VERSION 5.7 ;
  NOWIREEXTENSIONATPIN ON ;
  DIVIDERCHAR "/" ;
  BUSBITCHARS "[]" ;
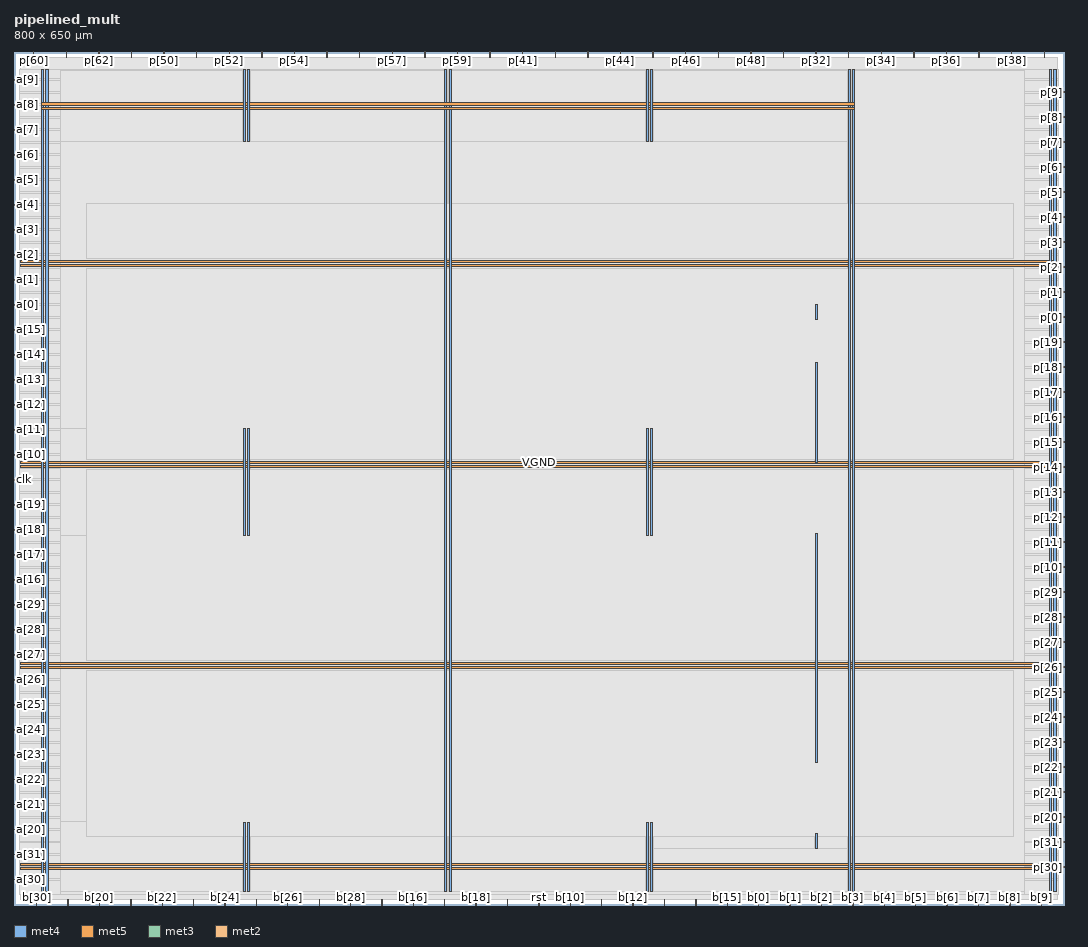
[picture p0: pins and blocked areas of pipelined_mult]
MACRO pipelined_mult
  CLASS BLOCK ;
  FOREIGN pipelined_mult ;
  ORIGIN 0.000 0.000 ;
  SIZE 800.000 BY 650.000 ;
  PIN VGND
    DIRECTION INOUT ;
    USE GROUND ;
    PORT
      LAYER met4 ;
        RECT 24.340 10.640 25.940 636.720 ;
    END
    PORT
      LAYER met4 ;
        RECT 177.940 10.640 179.540 62.995 ;
    END
    PORT
      LAYER met4 ;
        RECT 177.940 281.805 179.540 362.995 ;
    END
    PORT
      LAYER met4 ;
        RECT 177.940 581.805 179.540 636.720 ;
    END
    PORT
      LAYER met4 ;
        RECT 331.540 10.640 333.140 636.720 ;
    END
    PORT
      LAYER met4 ;
        RECT 485.140 10.640 486.740 62.995 ;
    END
    PORT
      LAYER met4 ;
        RECT 485.140 281.805 486.740 362.995 ;
    END
    PORT
      LAYER met4 ;
        RECT 485.140 581.805 486.740 636.720 ;
    END
    PORT
      LAYER met4 ;
        RECT 638.740 10.640 640.340 636.720 ;
    END
    PORT
      LAYER met4 ;
        RECT 792.340 10.640 793.940 636.720 ;
    END
    PORT
      LAYER met5 ;
        RECT 5.280 30.030 794.660 31.630 ;
    END
    PORT
      LAYER met5 ;
        RECT 5.280 183.210 794.660 184.810 ;
    END
    PORT
      LAYER met5 ;
        RECT 5.280 336.390 794.660 337.990 ;
    END
    PORT
      LAYER met5 ;
        RECT 5.280 489.570 794.660 491.170 ;
    END
    PORT
      LAYER met4 ;
        RECT 610.540 43.280 612.140 54.640 ;
    END
    PORT
      LAYER met4 ;
        RECT 610.540 108.560 612.140 283.120 ;
    END
    PORT
      LAYER met4 ;
        RECT 610.540 337.040 612.140 413.680 ;
    END
    PORT
      LAYER met4 ;
        RECT 610.540 445.840 612.140 457.200 ;
    END
    PORT
      LAYER met5 ;
        RECT 21.040 609.500 640.340 611.100 ;
    END
  END VGND
  PIN VPWR
    DIRECTION INOUT ;
    USE POWER ;
    PORT
      LAYER met4 ;
        RECT 21.040 10.640 22.640 636.720 ;
    END
    PORT
      LAYER met4 ;
        RECT 174.640 10.640 176.240 62.995 ;
    END
    PORT
      LAYER met4 ;
        RECT 174.640 281.805 176.240 362.995 ;
    END
    PORT
      LAYER met4 ;
        RECT 174.640 581.805 176.240 636.720 ;
    END
    PORT
      LAYER met4 ;
        RECT 328.240 10.640 329.840 636.720 ;
    END
    PORT
      LAYER met4 ;
        RECT 481.840 10.640 483.440 62.995 ;
    END
    PORT
      LAYER met4 ;
        RECT 481.840 281.805 483.440 362.995 ;
    END
    PORT
      LAYER met4 ;
        RECT 481.840 581.805 483.440 636.720 ;
    END
    PORT
      LAYER met4 ;
        RECT 635.440 10.640 637.040 636.720 ;
    END
    PORT
      LAYER met4 ;
        RECT 789.040 10.640 790.640 636.720 ;
    END
    PORT
      LAYER met5 ;
        RECT 5.280 26.730 794.660 28.330 ;
    END
    PORT
      LAYER met5 ;
        RECT 5.280 179.910 794.660 181.510 ;
    END
    PORT
      LAYER met5 ;
        RECT 5.280 333.090 794.660 334.690 ;
    END
    PORT
      LAYER met5 ;
        RECT 5.280 486.270 794.660 487.870 ;
    END
    PORT
      LAYER met5 ;
        RECT 21.040 606.100 640.340 607.700 ;
    END
  END VPWR
  PIN a[0]
    DIRECTION INPUT ;
    USE SIGNAL ;
    ANTENNAGATEAREA 0.682200 ;
    ANTENNADIFFAREA 0.434700 ;
    PORT
      LAYER met3 ;
        RECT 0.000 457.000 4.000 457.600 ;
    END
  END a[0]
  PIN a[10]
    DIRECTION INPUT ;
    USE SIGNAL ;
    ANTENNAGATEAREA 0.647700 ;
    ANTENNADIFFAREA 0.434700 ;
    PORT
      LAYER met3 ;
        RECT 0.000 342.760 4.000 343.360 ;
    END
  END a[10]
  PIN a[11]
    DIRECTION INPUT ;
    USE SIGNAL ;
    ANTENNAGATEAREA 0.647700 ;
    ANTENNADIFFAREA 0.434700 ;
    PORT
      LAYER met3 ;
        RECT 0.000 361.800 4.000 362.400 ;
    END
  END a[11]
  PIN a[12]
    DIRECTION INPUT ;
    USE SIGNAL ;
    ANTENNAGATEAREA 0.682200 ;
    ANTENNADIFFAREA 0.434700 ;
    PORT
      LAYER met3 ;
        RECT 0.000 380.840 4.000 381.440 ;
    END
  END a[12]
  PIN a[13]
    DIRECTION INPUT ;
    USE SIGNAL ;
    ANTENNAGATEAREA 0.647700 ;
    ANTENNADIFFAREA 0.434700 ;
    PORT
      LAYER met3 ;
        RECT 0.000 399.880 4.000 400.480 ;
    END
  END a[13]
  PIN a[14]
    DIRECTION INPUT ;
    USE SIGNAL ;
    ANTENNAGATEAREA 0.647700 ;
    ANTENNADIFFAREA 0.434700 ;
    PORT
      LAYER met3 ;
        RECT 0.000 418.920 4.000 419.520 ;
    END
  END a[14]
  PIN a[15]
    DIRECTION INPUT ;
    USE SIGNAL ;
    ANTENNAGATEAREA 0.647700 ;
    ANTENNADIFFAREA 0.434700 ;
    PORT
      LAYER met3 ;
        RECT 0.000 437.960 4.000 438.560 ;
    END
  END a[15]
  PIN a[16]
    DIRECTION INPUT ;
    USE SIGNAL ;
    ANTENNAGATEAREA 0.647700 ;
    ANTENNADIFFAREA 0.434700 ;
    PORT
      LAYER met3 ;
        RECT 0.000 247.560 4.000 248.160 ;
    END
  END a[16]
  PIN a[17]
    DIRECTION INPUT ;
    USE SIGNAL ;
    ANTENNAGATEAREA 0.647700 ;
    ANTENNADIFFAREA 0.434700 ;
    PORT
      LAYER met3 ;
        RECT 0.000 266.600 4.000 267.200 ;
    END
  END a[17]
  PIN a[18]
    DIRECTION INPUT ;
    USE SIGNAL ;
    ANTENNAGATEAREA 0.682200 ;
    ANTENNADIFFAREA 0.434700 ;
    PORT
      LAYER met3 ;
        RECT 0.000 285.640 4.000 286.240 ;
    END
  END a[18]
  PIN a[19]
    DIRECTION INPUT ;
    USE SIGNAL ;
    ANTENNAGATEAREA 0.682200 ;
    ANTENNADIFFAREA 0.434700 ;
    PORT
      LAYER met3 ;
        RECT 0.000 304.680 4.000 305.280 ;
    END
  END a[19]
  PIN a[1]
    DIRECTION INPUT ;
    USE SIGNAL ;
    ANTENNAGATEAREA 0.682200 ;
    ANTENNADIFFAREA 0.434700 ;
    PORT
      LAYER met3 ;
        RECT 0.000 476.040 4.000 476.640 ;
    END
  END a[1]
  PIN a[20]
    DIRECTION INPUT ;
    USE SIGNAL ;
    ANTENNAGATEAREA 0.682200 ;
    ANTENNADIFFAREA 0.434700 ;
    PORT
      LAYER met3 ;
        RECT 0.000 57.160 4.000 57.760 ;
    END
  END a[20]
  PIN a[21]
    DIRECTION INPUT ;
    USE SIGNAL ;
    ANTENNAGATEAREA 0.682200 ;
    ANTENNADIFFAREA 0.434700 ;
    PORT
      LAYER met3 ;
        RECT 0.000 76.200 4.000 76.800 ;
    END
  END a[21]
  PIN a[22]
    DIRECTION INPUT ;
    USE SIGNAL ;
    ANTENNAGATEAREA 0.682200 ;
    ANTENNADIFFAREA 0.434700 ;
    PORT
      LAYER met3 ;
        RECT 0.000 95.240 4.000 95.840 ;
    END
  END a[22]
  PIN a[23]
    DIRECTION INPUT ;
    USE SIGNAL ;
    ANTENNAGATEAREA 0.860700 ;
    ANTENNADIFFAREA 0.434700 ;
    PORT
      LAYER met3 ;
        RECT 0.000 114.280 4.000 114.880 ;
    END
  END a[23]
  PIN a[24]
    DIRECTION INPUT ;
    USE SIGNAL ;
    ANTENNAGATEAREA 0.682200 ;
    ANTENNADIFFAREA 0.434700 ;
    PORT
      LAYER met3 ;
        RECT 0.000 133.320 4.000 133.920 ;
    END
  END a[24]
  PIN a[25]
    DIRECTION INPUT ;
    USE SIGNAL ;
    ANTENNAGATEAREA 0.647700 ;
    ANTENNADIFFAREA 0.434700 ;
    PORT
      LAYER met3 ;
        RECT 0.000 152.360 4.000 152.960 ;
    END
  END a[25]
  PIN a[26]
    DIRECTION INPUT ;
    USE SIGNAL ;
    ANTENNAGATEAREA 0.647700 ;
    ANTENNADIFFAREA 0.434700 ;
    PORT
      LAYER met3 ;
        RECT 0.000 171.400 4.000 172.000 ;
    END
  END a[26]
  PIN a[27]
    DIRECTION INPUT ;
    USE SIGNAL ;
    ANTENNAGATEAREA 0.647700 ;
    ANTENNADIFFAREA 0.434700 ;
    PORT
      LAYER met3 ;
        RECT 0.000 190.440 4.000 191.040 ;
    END
  END a[27]
  PIN a[28]
    DIRECTION INPUT ;
    USE SIGNAL ;
    ANTENNAGATEAREA 0.682200 ;
    ANTENNADIFFAREA 0.434700 ;
    PORT
      LAYER met3 ;
        RECT 0.000 209.480 4.000 210.080 ;
    END
  END a[28]
  PIN a[29]
    DIRECTION INPUT ;
    USE SIGNAL ;
    ANTENNAGATEAREA 0.647700 ;
    ANTENNADIFFAREA 0.434700 ;
    PORT
      LAYER met3 ;
        RECT 0.000 228.520 4.000 229.120 ;
    END
  END a[29]
  PIN a[2]
    DIRECTION INPUT ;
    USE SIGNAL ;
    ANTENNAGATEAREA 0.682200 ;
    ANTENNADIFFAREA 0.434700 ;
    PORT
      LAYER met3 ;
        RECT 0.000 495.080 4.000 495.680 ;
    END
  END a[2]
  PIN a[30]
    DIRECTION INPUT ;
    USE SIGNAL ;
    ANTENNAGATEAREA 0.682200 ;
    ANTENNADIFFAREA 0.434700 ;
    PORT
      LAYER met3 ;
        RECT 0.000 19.080 4.000 19.680 ;
    END
  END a[30]
  PIN a[31]
    DIRECTION INPUT ;
    USE SIGNAL ;
    ANTENNAGATEAREA 0.682200 ;
    ANTENNADIFFAREA 0.434700 ;
    PORT
      LAYER met3 ;
        RECT 0.000 38.120 4.000 38.720 ;
    END
  END a[31]
  PIN a[3]
    DIRECTION INPUT ;
    USE SIGNAL ;
    ANTENNAGATEAREA 0.682200 ;
    ANTENNADIFFAREA 0.434700 ;
    PORT
      LAYER met3 ;
        RECT 0.000 514.120 4.000 514.720 ;
    END
  END a[3]
  PIN a[4]
    DIRECTION INPUT ;
    USE SIGNAL ;
    ANTENNAGATEAREA 0.682200 ;
    ANTENNADIFFAREA 0.434700 ;
    PORT
      LAYER met3 ;
        RECT 0.000 533.160 4.000 533.760 ;
    END
  END a[4]
  PIN a[5]
    DIRECTION INPUT ;
    USE SIGNAL ;
    ANTENNAGATEAREA 0.682200 ;
    ANTENNADIFFAREA 0.434700 ;
    PORT
      LAYER met3 ;
        RECT 0.000 552.200 4.000 552.800 ;
    END
  END a[5]
  PIN a[6]
    DIRECTION INPUT ;
    USE SIGNAL ;
    ANTENNAGATEAREA 0.682200 ;
    ANTENNADIFFAREA 0.434700 ;
    PORT
      LAYER met3 ;
        RECT 0.000 571.240 4.000 571.840 ;
    END
  END a[6]
  PIN a[7]
    DIRECTION INPUT ;
    USE SIGNAL ;
    ANTENNAGATEAREA 0.682200 ;
    ANTENNADIFFAREA 0.434700 ;
    PORT
      LAYER met3 ;
        RECT 0.000 590.280 4.000 590.880 ;
    END
  END a[7]
  PIN a[8]
    DIRECTION INPUT ;
    USE SIGNAL ;
    ANTENNAGATEAREA 0.860700 ;
    ANTENNADIFFAREA 0.434700 ;
    PORT
      LAYER met3 ;
        RECT 0.000 609.320 4.000 609.920 ;
    END
  END a[8]
  PIN a[9]
    DIRECTION INPUT ;
    USE SIGNAL ;
    ANTENNAGATEAREA 0.682200 ;
    ANTENNADIFFAREA 0.434700 ;
    PORT
      LAYER met3 ;
        RECT 0.000 628.360 4.000 628.960 ;
    END
  END a[9]
  PIN b[0]
    DIRECTION INPUT ;
    USE SIGNAL ;
    ANTENNAGATEAREA 0.647700 ;
    ANTENNADIFFAREA 0.434700 ;
    PORT
      LAYER met2 ;
        RECT 567.270 0.000 567.550 4.000 ;
    END
  END b[0]
  PIN b[10]
    DIRECTION INPUT ;
    USE SIGNAL ;
    ANTENNAGATEAREA 0.682200 ;
    ANTENNADIFFAREA 0.434700 ;
    PORT
      LAYER met2 ;
        RECT 423.750 0.000 424.030 4.000 ;
    END
  END b[10]
  PIN b[11]
    DIRECTION INPUT ;
    USE SIGNAL ;
    ANTENNAGATEAREA 0.682200 ;
    ANTENNADIFFAREA 0.434700 ;
    PORT
      LAYER met2 ;
        RECT 447.670 0.000 447.950 4.000 ;
    END
  END b[11]
  PIN b[12]
    DIRECTION INPUT ;
    USE SIGNAL ;
    ANTENNAGATEAREA 0.682200 ;
    ANTENNADIFFAREA 0.434700 ;
    PORT
      LAYER met2 ;
        RECT 471.590 0.000 471.870 4.000 ;
    END
  END b[12]
  PIN b[13]
    DIRECTION INPUT ;
    USE SIGNAL ;
    ANTENNAGATEAREA 0.682200 ;
    ANTENNADIFFAREA 0.434700 ;
    PORT
      LAYER met2 ;
        RECT 495.510 0.000 495.790 4.000 ;
    END
  END b[13]
  PIN b[14]
    DIRECTION INPUT ;
    USE SIGNAL ;
    ANTENNAGATEAREA 0.682200 ;
    ANTENNADIFFAREA 0.434700 ;
    PORT
      LAYER met2 ;
        RECT 519.430 0.000 519.710 4.000 ;
    END
  END b[14]
  PIN b[15]
    DIRECTION INPUT ;
    USE SIGNAL ;
    ANTENNAGATEAREA 0.682200 ;
    ANTENNADIFFAREA 0.434700 ;
    PORT
      LAYER met2 ;
        RECT 543.350 0.000 543.630 4.000 ;
    END
  END b[15]
  PIN b[16]
    DIRECTION INPUT ;
    USE SIGNAL ;
    ANTENNAGATEAREA 0.647700 ;
    ANTENNADIFFAREA 0.434700 ;
    PORT
      LAYER met2 ;
        RECT 304.150 0.000 304.430 4.000 ;
    END
  END b[16]
  PIN b[17]
    DIRECTION INPUT ;
    USE SIGNAL ;
    ANTENNAGATEAREA 0.682200 ;
    ANTENNADIFFAREA 0.434700 ;
    PORT
      LAYER met2 ;
        RECT 328.070 0.000 328.350 4.000 ;
    END
  END b[17]
  PIN b[18]
    DIRECTION INPUT ;
    USE SIGNAL ;
    ANTENNAGATEAREA 0.682200 ;
    ANTENNADIFFAREA 0.434700 ;
    PORT
      LAYER met2 ;
        RECT 351.990 0.000 352.270 4.000 ;
    END
  END b[18]
  PIN b[19]
    DIRECTION INPUT ;
    USE SIGNAL ;
    ANTENNAGATEAREA 0.860700 ;
    ANTENNADIFFAREA 0.434700 ;
    PORT
      LAYER met2 ;
        RECT 375.910 0.000 376.190 4.000 ;
    END
  END b[19]
  PIN b[1]
    DIRECTION INPUT ;
    USE SIGNAL ;
    ANTENNAGATEAREA 0.647700 ;
    ANTENNADIFFAREA 0.434700 ;
    PORT
      LAYER met2 ;
        RECT 591.190 0.000 591.470 4.000 ;
    END
  END b[1]
  PIN b[20]
    DIRECTION INPUT ;
    USE SIGNAL ;
    ANTENNAGATEAREA 0.682200 ;
    ANTENNADIFFAREA 0.434700 ;
    PORT
      LAYER met2 ;
        RECT 64.950 0.000 65.230 4.000 ;
    END
  END b[20]
  PIN b[21]
    DIRECTION INPUT ;
    USE SIGNAL ;
    ANTENNAGATEAREA 0.682200 ;
    ANTENNADIFFAREA 0.434700 ;
    PORT
      LAYER met2 ;
        RECT 88.870 0.000 89.150 4.000 ;
    END
  END b[21]
  PIN b[22]
    DIRECTION INPUT ;
    USE SIGNAL ;
    ANTENNAGATEAREA 0.682200 ;
    ANTENNADIFFAREA 0.434700 ;
    PORT
      LAYER met2 ;
        RECT 112.790 0.000 113.070 4.000 ;
    END
  END b[22]
  PIN b[23]
    DIRECTION INPUT ;
    USE SIGNAL ;
    ANTENNAGATEAREA 0.682200 ;
    ANTENNADIFFAREA 0.434700 ;
    PORT
      LAYER met2 ;
        RECT 136.710 0.000 136.990 4.000 ;
    END
  END b[23]
  PIN b[24]
    DIRECTION INPUT ;
    USE SIGNAL ;
    ANTENNAGATEAREA 0.682200 ;
    ANTENNADIFFAREA 0.434700 ;
    PORT
      LAYER met2 ;
        RECT 160.630 0.000 160.910 4.000 ;
    END
  END b[24]
  PIN b[25]
    DIRECTION INPUT ;
    USE SIGNAL ;
    ANTENNAGATEAREA 0.682200 ;
    ANTENNADIFFAREA 0.434700 ;
    PORT
      LAYER met2 ;
        RECT 184.550 0.000 184.830 4.000 ;
    END
  END b[25]
  PIN b[26]
    DIRECTION INPUT ;
    USE SIGNAL ;
    ANTENNAGATEAREA 0.682200 ;
    ANTENNADIFFAREA 0.434700 ;
    PORT
      LAYER met2 ;
        RECT 208.470 0.000 208.750 4.000 ;
    END
  END b[26]
  PIN b[27]
    DIRECTION INPUT ;
    USE SIGNAL ;
    ANTENNAGATEAREA 0.682200 ;
    ANTENNADIFFAREA 0.434700 ;
    PORT
      LAYER met2 ;
        RECT 232.390 0.000 232.670 4.000 ;
    END
  END b[27]
  PIN b[28]
    DIRECTION INPUT ;
    USE SIGNAL ;
    ANTENNAGATEAREA 0.682200 ;
    ANTENNADIFFAREA 0.434700 ;
    PORT
      LAYER met2 ;
        RECT 256.310 0.000 256.590 4.000 ;
    END
  END b[28]
  PIN b[29]
    DIRECTION INPUT ;
    USE SIGNAL ;
    ANTENNAGATEAREA 0.682200 ;
    ANTENNADIFFAREA 0.434700 ;
    PORT
      LAYER met2 ;
        RECT 280.230 0.000 280.510 4.000 ;
    END
  END b[29]
  PIN b[2]
    DIRECTION INPUT ;
    USE SIGNAL ;
    ANTENNAGATEAREA 0.682200 ;
    ANTENNADIFFAREA 0.434700 ;
    PORT
      LAYER met2 ;
        RECT 615.110 0.000 615.390 4.000 ;
    END
  END b[2]
  PIN b[30]
    DIRECTION INPUT ;
    USE SIGNAL ;
    ANTENNAGATEAREA 0.682200 ;
    ANTENNADIFFAREA 0.434700 ;
    PORT
      LAYER met2 ;
        RECT 17.110 0.000 17.390 4.000 ;
    END
  END b[30]
  PIN b[31]
    DIRECTION INPUT ;
    USE SIGNAL ;
    ANTENNAGATEAREA 0.682200 ;
    ANTENNADIFFAREA 0.434700 ;
    PORT
      LAYER met2 ;
        RECT 41.030 0.000 41.310 4.000 ;
    END
  END b[31]
  PIN b[3]
    DIRECTION INPUT ;
    USE SIGNAL ;
    ANTENNAGATEAREA 0.860700 ;
    ANTENNADIFFAREA 0.434700 ;
    PORT
      LAYER met2 ;
        RECT 639.030 0.000 639.310 4.000 ;
    END
  END b[3]
  PIN b[4]
    DIRECTION INPUT ;
    USE SIGNAL ;
    ANTENNAGATEAREA 0.860700 ;
    ANTENNADIFFAREA 0.434700 ;
    PORT
      LAYER met2 ;
        RECT 662.950 0.000 663.230 4.000 ;
    END
  END b[4]
  PIN b[5]
    DIRECTION INPUT ;
    USE SIGNAL ;
    ANTENNAGATEAREA 0.860700 ;
    ANTENNADIFFAREA 0.434700 ;
    PORT
      LAYER met2 ;
        RECT 686.870 0.000 687.150 4.000 ;
    END
  END b[5]
  PIN b[6]
    DIRECTION INPUT ;
    USE SIGNAL ;
    ANTENNAGATEAREA 0.860700 ;
    ANTENNADIFFAREA 0.434700 ;
    PORT
      LAYER met2 ;
        RECT 710.790 0.000 711.070 4.000 ;
    END
  END b[6]
  PIN b[7]
    DIRECTION INPUT ;
    USE SIGNAL ;
    ANTENNAGATEAREA 0.860700 ;
    ANTENNADIFFAREA 0.434700 ;
    PORT
      LAYER met2 ;
        RECT 734.710 0.000 734.990 4.000 ;
    END
  END b[7]
  PIN b[8]
    DIRECTION INPUT ;
    USE SIGNAL ;
    ANTENNAGATEAREA 0.929700 ;
    ANTENNADIFFAREA 0.434700 ;
    PORT
      LAYER met2 ;
        RECT 758.630 0.000 758.910 4.000 ;
    END
  END b[8]
  PIN b[9]
    DIRECTION INPUT ;
    USE SIGNAL ;
    ANTENNAGATEAREA 0.929700 ;
    ANTENNADIFFAREA 0.434700 ;
    PORT
      LAYER met2 ;
        RECT 782.550 0.000 782.830 4.000 ;
    END
  END b[9]
  PIN clk
    DIRECTION INPUT ;
    USE SIGNAL ;
    ANTENNAGATEAREA 2.573400 ;
    ANTENNADIFFAREA 0.869400 ;
    PORT
      LAYER met3 ;
        RECT 0.000 323.720 4.000 324.320 ;
    END
  END clk
  PIN p[0]
    DIRECTION OUTPUT ;
    USE SIGNAL ;
    ANTENNADIFFAREA 0.445500 ;
    PORT
      LAYER met3 ;
        RECT 796.000 447.480 800.000 448.080 ;
    END
  END p[0]
  PIN p[10]
    DIRECTION OUTPUT ;
    USE SIGNAL ;
    ANTENNADIFFAREA 0.445500 ;
    PORT
      LAYER met3 ;
        RECT 796.000 257.080 800.000 257.680 ;
    END
  END p[10]
  PIN p[11]
    DIRECTION OUTPUT ;
    USE SIGNAL ;
    ANTENNADIFFAREA 0.445500 ;
    PORT
      LAYER met3 ;
        RECT 796.000 276.120 800.000 276.720 ;
    END
  END p[11]
  PIN p[12]
    DIRECTION OUTPUT ;
    USE SIGNAL ;
    ANTENNADIFFAREA 0.445500 ;
    PORT
      LAYER met3 ;
        RECT 796.000 295.160 800.000 295.760 ;
    END
  END p[12]
  PIN p[13]
    DIRECTION OUTPUT ;
    USE SIGNAL ;
    ANTENNADIFFAREA 0.445500 ;
    PORT
      LAYER met3 ;
        RECT 796.000 314.200 800.000 314.800 ;
    END
  END p[13]
  PIN p[14]
    DIRECTION OUTPUT ;
    USE SIGNAL ;
    ANTENNADIFFAREA 0.445500 ;
    PORT
      LAYER met3 ;
        RECT 796.000 333.240 800.000 333.840 ;
    END
  END p[14]
  PIN p[15]
    DIRECTION OUTPUT ;
    USE SIGNAL ;
    ANTENNADIFFAREA 0.445500 ;
    PORT
      LAYER met3 ;
        RECT 796.000 352.280 800.000 352.880 ;
    END
  END p[15]
  PIN p[16]
    DIRECTION OUTPUT ;
    USE SIGNAL ;
    ANTENNADIFFAREA 0.445500 ;
    PORT
      LAYER met3 ;
        RECT 796.000 371.320 800.000 371.920 ;
    END
  END p[16]
  PIN p[17]
    DIRECTION OUTPUT ;
    USE SIGNAL ;
    ANTENNADIFFAREA 0.445500 ;
    PORT
      LAYER met3 ;
        RECT 796.000 390.360 800.000 390.960 ;
    END
  END p[17]
  PIN p[18]
    DIRECTION OUTPUT ;
    USE SIGNAL ;
    ANTENNADIFFAREA 0.445500 ;
    PORT
      LAYER met3 ;
        RECT 796.000 409.400 800.000 410.000 ;
    END
  END p[18]
  PIN p[19]
    DIRECTION OUTPUT ;
    USE SIGNAL ;
    ANTENNADIFFAREA 0.445500 ;
    PORT
      LAYER met3 ;
        RECT 796.000 428.440 800.000 429.040 ;
    END
  END p[19]
  PIN p[1]
    DIRECTION OUTPUT ;
    USE SIGNAL ;
    ANTENNADIFFAREA 0.445500 ;
    PORT
      LAYER met3 ;
        RECT 796.000 466.520 800.000 467.120 ;
    END
  END p[1]
  PIN p[20]
    DIRECTION OUTPUT ;
    USE SIGNAL ;
    ANTENNADIFFAREA 0.445500 ;
    PORT
      LAYER met3 ;
        RECT 796.000 66.680 800.000 67.280 ;
    END
  END p[20]
  PIN p[21]
    DIRECTION OUTPUT ;
    USE SIGNAL ;
    ANTENNADIFFAREA 0.445500 ;
    PORT
      LAYER met3 ;
        RECT 796.000 85.720 800.000 86.320 ;
    END
  END p[21]
  PIN p[22]
    DIRECTION OUTPUT ;
    USE SIGNAL ;
    ANTENNADIFFAREA 0.445500 ;
    PORT
      LAYER met3 ;
        RECT 796.000 104.760 800.000 105.360 ;
    END
  END p[22]
  PIN p[23]
    DIRECTION OUTPUT ;
    USE SIGNAL ;
    ANTENNADIFFAREA 0.445500 ;
    PORT
      LAYER met3 ;
        RECT 796.000 123.800 800.000 124.400 ;
    END
  END p[23]
  PIN p[24]
    DIRECTION OUTPUT ;
    USE SIGNAL ;
    ANTENNADIFFAREA 0.445500 ;
    PORT
      LAYER met3 ;
        RECT 796.000 142.840 800.000 143.440 ;
    END
  END p[24]
  PIN p[25]
    DIRECTION OUTPUT ;
    USE SIGNAL ;
    ANTENNADIFFAREA 0.445500 ;
    PORT
      LAYER met3 ;
        RECT 796.000 161.880 800.000 162.480 ;
    END
  END p[25]
  PIN p[26]
    DIRECTION OUTPUT ;
    USE SIGNAL ;
    ANTENNADIFFAREA 0.445500 ;
    PORT
      LAYER met3 ;
        RECT 796.000 180.920 800.000 181.520 ;
    END
  END p[26]
  PIN p[27]
    DIRECTION OUTPUT ;
    USE SIGNAL ;
    ANTENNADIFFAREA 0.445500 ;
    PORT
      LAYER met3 ;
        RECT 796.000 199.960 800.000 200.560 ;
    END
  END p[27]
  PIN p[28]
    DIRECTION OUTPUT ;
    USE SIGNAL ;
    ANTENNADIFFAREA 0.445500 ;
    PORT
      LAYER met3 ;
        RECT 796.000 219.000 800.000 219.600 ;
    END
  END p[28]
  PIN p[29]
    DIRECTION OUTPUT ;
    USE SIGNAL ;
    ANTENNADIFFAREA 0.445500 ;
    PORT
      LAYER met3 ;
        RECT 796.000 238.040 800.000 238.640 ;
    END
  END p[29]
  PIN p[2]
    DIRECTION OUTPUT ;
    USE SIGNAL ;
    ANTENNADIFFAREA 0.445500 ;
    PORT
      LAYER met3 ;
        RECT 796.000 485.560 800.000 486.160 ;
    END
  END p[2]
  PIN p[30]
    DIRECTION OUTPUT ;
    USE SIGNAL ;
    ANTENNADIFFAREA 0.445500 ;
    PORT
      LAYER met3 ;
        RECT 796.000 28.600 800.000 29.200 ;
    END
  END p[30]
  PIN p[31]
    DIRECTION OUTPUT ;
    USE SIGNAL ;
    ANTENNADIFFAREA 0.445500 ;
    PORT
      LAYER met3 ;
        RECT 796.000 47.640 800.000 48.240 ;
    END
  END p[31]
  PIN p[32]
    DIRECTION OUTPUT ;
    USE SIGNAL ;
    ANTENNADIFFAREA 0.445500 ;
    PORT
      LAYER met2 ;
        RECT 610.970 646.000 611.250 650.000 ;
    END
  END p[32]
  PIN p[33]
    DIRECTION OUTPUT ;
    USE SIGNAL ;
    ANTENNADIFFAREA 0.445500 ;
    PORT
      LAYER met2 ;
        RECT 635.810 646.000 636.090 650.000 ;
    END
  END p[33]
  PIN p[34]
    DIRECTION OUTPUT ;
    USE SIGNAL ;
    ANTENNADIFFAREA 0.445500 ;
    PORT
      LAYER met2 ;
        RECT 660.650 646.000 660.930 650.000 ;
    END
  END p[34]
  PIN p[35]
    DIRECTION OUTPUT ;
    USE SIGNAL ;
    ANTENNADIFFAREA 0.445500 ;
    PORT
      LAYER met2 ;
        RECT 685.490 646.000 685.770 650.000 ;
    END
  END p[35]
  PIN p[36]
    DIRECTION OUTPUT ;
    USE SIGNAL ;
    ANTENNADIFFAREA 0.445500 ;
    PORT
      LAYER met2 ;
        RECT 710.330 646.000 710.610 650.000 ;
    END
  END p[36]
  PIN p[37]
    DIRECTION OUTPUT ;
    USE SIGNAL ;
    ANTENNADIFFAREA 0.445500 ;
    PORT
      LAYER met2 ;
        RECT 735.170 646.000 735.450 650.000 ;
    END
  END p[37]
  PIN p[38]
    DIRECTION OUTPUT ;
    USE SIGNAL ;
    ANTENNADIFFAREA 0.445500 ;
    PORT
      LAYER met2 ;
        RECT 760.010 646.000 760.290 650.000 ;
    END
  END p[38]
  PIN p[39]
    DIRECTION OUTPUT ;
    USE SIGNAL ;
    ANTENNADIFFAREA 0.445500 ;
    PORT
      LAYER met2 ;
        RECT 784.850 646.000 785.130 650.000 ;
    END
  END p[39]
  PIN p[3]
    DIRECTION OUTPUT ;
    USE SIGNAL ;
    ANTENNADIFFAREA 0.445500 ;
    PORT
      LAYER met3 ;
        RECT 796.000 504.600 800.000 505.200 ;
    END
  END p[3]
  PIN p[40]
    DIRECTION OUTPUT ;
    USE SIGNAL ;
    ANTENNADIFFAREA 0.445500 ;
    PORT
      LAYER met2 ;
        RECT 362.570 646.000 362.850 650.000 ;
    END
  END p[40]
  PIN p[41]
    DIRECTION OUTPUT ;
    USE SIGNAL ;
    ANTENNADIFFAREA 0.445500 ;
    PORT
      LAYER met2 ;
        RECT 387.410 646.000 387.690 650.000 ;
    END
  END p[41]
  PIN p[42]
    DIRECTION OUTPUT ;
    USE SIGNAL ;
    ANTENNADIFFAREA 0.445500 ;
    PORT
      LAYER met2 ;
        RECT 412.250 646.000 412.530 650.000 ;
    END
  END p[42]
  PIN p[43]
    DIRECTION OUTPUT ;
    USE SIGNAL ;
    ANTENNADIFFAREA 0.445500 ;
    PORT
      LAYER met2 ;
        RECT 437.090 646.000 437.370 650.000 ;
    END
  END p[43]
  PIN p[44]
    DIRECTION OUTPUT ;
    USE SIGNAL ;
    ANTENNADIFFAREA 0.445500 ;
    PORT
      LAYER met2 ;
        RECT 461.930 646.000 462.210 650.000 ;
    END
  END p[44]
  PIN p[45]
    DIRECTION OUTPUT ;
    USE SIGNAL ;
    ANTENNADIFFAREA 0.445500 ;
    PORT
      LAYER met2 ;
        RECT 486.770 646.000 487.050 650.000 ;
    END
  END p[45]
  PIN p[46]
    DIRECTION OUTPUT ;
    USE SIGNAL ;
    ANTENNADIFFAREA 0.445500 ;
    PORT
      LAYER met2 ;
        RECT 511.610 646.000 511.890 650.000 ;
    END
  END p[46]
  PIN p[47]
    DIRECTION OUTPUT ;
    USE SIGNAL ;
    ANTENNADIFFAREA 0.445500 ;
    PORT
      LAYER met2 ;
        RECT 536.450 646.000 536.730 650.000 ;
    END
  END p[47]
  PIN p[48]
    DIRECTION OUTPUT ;
    USE SIGNAL ;
    ANTENNADIFFAREA 0.445500 ;
    PORT
      LAYER met2 ;
        RECT 561.290 646.000 561.570 650.000 ;
    END
  END p[48]
  PIN p[49]
    DIRECTION OUTPUT ;
    USE SIGNAL ;
    ANTENNADIFFAREA 0.445500 ;
    PORT
      LAYER met2 ;
        RECT 586.130 646.000 586.410 650.000 ;
    END
  END p[49]
  PIN p[4]
    DIRECTION OUTPUT ;
    USE SIGNAL ;
    ANTENNADIFFAREA 0.445500 ;
    PORT
      LAYER met3 ;
        RECT 796.000 523.640 800.000 524.240 ;
    END
  END p[4]
  PIN p[50]
    DIRECTION OUTPUT ;
    USE SIGNAL ;
    ANTENNADIFFAREA 0.445500 ;
    PORT
      LAYER met2 ;
        RECT 114.170 646.000 114.450 650.000 ;
    END
  END p[50]
  PIN p[51]
    DIRECTION OUTPUT ;
    USE SIGNAL ;
    ANTENNADIFFAREA 0.445500 ;
    PORT
      LAYER met2 ;
        RECT 139.010 646.000 139.290 650.000 ;
    END
  END p[51]
  PIN p[52]
    DIRECTION OUTPUT ;
    USE SIGNAL ;
    ANTENNADIFFAREA 0.445500 ;
    PORT
      LAYER met2 ;
        RECT 163.850 646.000 164.130 650.000 ;
    END
  END p[52]
  PIN p[53]
    DIRECTION OUTPUT ;
    USE SIGNAL ;
    ANTENNADIFFAREA 0.445500 ;
    PORT
      LAYER met2 ;
        RECT 188.690 646.000 188.970 650.000 ;
    END
  END p[53]
  PIN p[54]
    DIRECTION OUTPUT ;
    USE SIGNAL ;
    ANTENNADIFFAREA 0.445500 ;
    PORT
      LAYER met2 ;
        RECT 213.530 646.000 213.810 650.000 ;
    END
  END p[54]
  PIN p[55]
    DIRECTION OUTPUT ;
    USE SIGNAL ;
    ANTENNADIFFAREA 0.445500 ;
    PORT
      LAYER met2 ;
        RECT 238.370 646.000 238.650 650.000 ;
    END
  END p[55]
  PIN p[56]
    DIRECTION OUTPUT ;
    USE SIGNAL ;
    ANTENNADIFFAREA 0.445500 ;
    PORT
      LAYER met2 ;
        RECT 263.210 646.000 263.490 650.000 ;
    END
  END p[56]
  PIN p[57]
    DIRECTION OUTPUT ;
    USE SIGNAL ;
    ANTENNADIFFAREA 0.445500 ;
    PORT
      LAYER met2 ;
        RECT 288.050 646.000 288.330 650.000 ;
    END
  END p[57]
  PIN p[58]
    DIRECTION OUTPUT ;
    USE SIGNAL ;
    ANTENNADIFFAREA 0.445500 ;
    PORT
      LAYER met2 ;
        RECT 312.890 646.000 313.170 650.000 ;
    END
  END p[58]
  PIN p[59]
    DIRECTION OUTPUT ;
    USE SIGNAL ;
    ANTENNADIFFAREA 0.445500 ;
    PORT
      LAYER met2 ;
        RECT 337.730 646.000 338.010 650.000 ;
    END
  END p[59]
  PIN p[5]
    DIRECTION OUTPUT ;
    USE SIGNAL ;
    ANTENNADIFFAREA 0.445500 ;
    PORT
      LAYER met3 ;
        RECT 796.000 542.680 800.000 543.280 ;
    END
  END p[5]
  PIN p[60]
    DIRECTION OUTPUT ;
    USE SIGNAL ;
    ANTENNADIFFAREA 0.445500 ;
    PORT
      LAYER met2 ;
        RECT 14.810 646.000 15.090 650.000 ;
    END
  END p[60]
  PIN p[61]
    DIRECTION OUTPUT ;
    USE SIGNAL ;
    ANTENNADIFFAREA 0.445500 ;
    PORT
      LAYER met2 ;
        RECT 39.650 646.000 39.930 650.000 ;
    END
  END p[61]
  PIN p[62]
    DIRECTION OUTPUT ;
    USE SIGNAL ;
    ANTENNADIFFAREA 0.445500 ;
    PORT
      LAYER met2 ;
        RECT 64.490 646.000 64.770 650.000 ;
    END
  END p[62]
  PIN p[63]
    DIRECTION OUTPUT ;
    USE SIGNAL ;
    ANTENNADIFFAREA 0.445500 ;
    PORT
      LAYER met2 ;
        RECT 89.330 646.000 89.610 650.000 ;
    END
  END p[63]
  PIN p[6]
    DIRECTION OUTPUT ;
    USE SIGNAL ;
    ANTENNADIFFAREA 0.445500 ;
    PORT
      LAYER met3 ;
        RECT 796.000 561.720 800.000 562.320 ;
    END
  END p[6]
  PIN p[7]
    DIRECTION OUTPUT ;
    USE SIGNAL ;
    ANTENNADIFFAREA 0.445500 ;
    PORT
      LAYER met3 ;
        RECT 796.000 580.760 800.000 581.360 ;
    END
  END p[7]
  PIN p[8]
    DIRECTION OUTPUT ;
    USE SIGNAL ;
    ANTENNADIFFAREA 0.445500 ;
    PORT
      LAYER met3 ;
        RECT 796.000 599.800 800.000 600.400 ;
    END
  END p[8]
  PIN p[9]
    DIRECTION OUTPUT ;
    USE SIGNAL ;
    ANTENNADIFFAREA 0.445500 ;
    PORT
      LAYER met3 ;
        RECT 796.000 618.840 800.000 619.440 ;
    END
  END p[9]
  PIN rst
    DIRECTION INPUT ;
    USE SIGNAL ;
    ANTENNAGATEAREA 1.424700 ;
    ANTENNADIFFAREA 0.434700 ;
    PORT
      LAYER met2 ;
        RECT 399.830 0.000 400.110 4.000 ;
    END
  END rst
  OBS
      LAYER nwell ;
        RECT 5.330 10.795 794.610 636.565 ;
      LAYER li1 ;
        RECT 5.520 10.795 794.420 636.565 ;
      LAYER met1 ;
        RECT 5.130 9.220 794.810 638.140 ;
      LAYER met2 ;
        RECT 5.150 645.720 14.530 646.000 ;
        RECT 15.370 645.720 39.370 646.000 ;
        RECT 40.210 645.720 64.210 646.000 ;
        RECT 65.050 645.720 89.050 646.000 ;
        RECT 89.890 645.720 113.890 646.000 ;
        RECT 114.730 645.720 138.730 646.000 ;
        RECT 139.570 645.720 163.570 646.000 ;
        RECT 164.410 645.720 188.410 646.000 ;
        RECT 189.250 645.720 213.250 646.000 ;
        RECT 214.090 645.720 238.090 646.000 ;
        RECT 238.930 645.720 262.930 646.000 ;
        RECT 263.770 645.720 287.770 646.000 ;
        RECT 288.610 645.720 312.610 646.000 ;
        RECT 313.450 645.720 337.450 646.000 ;
        RECT 338.290 645.720 362.290 646.000 ;
        RECT 363.130 645.720 387.130 646.000 ;
        RECT 387.970 645.720 411.970 646.000 ;
        RECT 412.810 645.720 436.810 646.000 ;
        RECT 437.650 645.720 461.650 646.000 ;
        RECT 462.490 645.720 486.490 646.000 ;
        RECT 487.330 645.720 511.330 646.000 ;
        RECT 512.170 645.720 536.170 646.000 ;
        RECT 537.010 645.720 561.010 646.000 ;
        RECT 561.850 645.720 585.850 646.000 ;
        RECT 586.690 645.720 610.690 646.000 ;
        RECT 611.530 645.720 635.530 646.000 ;
        RECT 636.370 645.720 660.370 646.000 ;
        RECT 661.210 645.720 685.210 646.000 ;
        RECT 686.050 645.720 710.050 646.000 ;
        RECT 710.890 645.720 734.890 646.000 ;
        RECT 735.730 645.720 759.730 646.000 ;
        RECT 760.570 645.720 784.570 646.000 ;
        RECT 785.410 645.720 794.790 646.000 ;
        RECT 5.150 4.280 794.790 645.720 ;
        RECT 5.150 4.000 16.830 4.280 ;
        RECT 17.670 4.000 40.750 4.280 ;
        RECT 41.590 4.000 64.670 4.280 ;
        RECT 65.510 4.000 88.590 4.280 ;
        RECT 89.430 4.000 112.510 4.280 ;
        RECT 113.350 4.000 136.430 4.280 ;
        RECT 137.270 4.000 160.350 4.280 ;
        RECT 161.190 4.000 184.270 4.280 ;
        RECT 185.110 4.000 208.190 4.280 ;
        RECT 209.030 4.000 232.110 4.280 ;
        RECT 232.950 4.000 256.030 4.280 ;
        RECT 256.870 4.000 279.950 4.280 ;
        RECT 280.790 4.000 303.870 4.280 ;
        RECT 304.710 4.000 327.790 4.280 ;
        RECT 328.630 4.000 351.710 4.280 ;
        RECT 352.550 4.000 375.630 4.280 ;
        RECT 376.470 4.000 399.550 4.280 ;
        RECT 400.390 4.000 423.470 4.280 ;
        RECT 424.310 4.000 447.390 4.280 ;
        RECT 448.230 4.000 471.310 4.280 ;
        RECT 472.150 4.000 495.230 4.280 ;
        RECT 496.070 4.000 519.150 4.280 ;
        RECT 519.990 4.000 543.070 4.280 ;
        RECT 543.910 4.000 566.990 4.280 ;
        RECT 567.830 4.000 590.910 4.280 ;
        RECT 591.750 4.000 614.830 4.280 ;
        RECT 615.670 4.000 638.750 4.280 ;
        RECT 639.590 4.000 662.670 4.280 ;
        RECT 663.510 4.000 686.590 4.280 ;
        RECT 687.430 4.000 710.510 4.280 ;
        RECT 711.350 4.000 734.430 4.280 ;
        RECT 735.270 4.000 758.350 4.280 ;
        RECT 759.190 4.000 782.270 4.280 ;
        RECT 783.110 4.000 794.790 4.280 ;
      LAYER met3 ;
        RECT 4.000 629.360 796.000 636.645 ;
        RECT 4.400 627.960 796.000 629.360 ;
        RECT 4.000 619.840 796.000 627.960 ;
        RECT 4.000 618.440 795.600 619.840 ;
        RECT 4.000 610.320 796.000 618.440 ;
        RECT 4.400 608.920 796.000 610.320 ;
        RECT 4.000 600.800 796.000 608.920 ;
        RECT 4.000 599.400 795.600 600.800 ;
        RECT 4.000 591.280 796.000 599.400 ;
        RECT 4.400 589.880 796.000 591.280 ;
        RECT 4.000 581.760 796.000 589.880 ;
        RECT 4.000 580.360 795.600 581.760 ;
        RECT 4.000 572.240 796.000 580.360 ;
        RECT 4.400 570.840 796.000 572.240 ;
        RECT 4.000 562.720 796.000 570.840 ;
        RECT 4.000 561.320 795.600 562.720 ;
        RECT 4.000 553.200 796.000 561.320 ;
        RECT 4.400 551.800 796.000 553.200 ;
        RECT 4.000 543.680 796.000 551.800 ;
        RECT 4.000 542.280 795.600 543.680 ;
        RECT 4.000 534.160 796.000 542.280 ;
        RECT 4.400 532.760 796.000 534.160 ;
        RECT 4.000 524.640 796.000 532.760 ;
        RECT 4.000 523.240 795.600 524.640 ;
        RECT 4.000 515.120 796.000 523.240 ;
        RECT 4.400 513.720 796.000 515.120 ;
        RECT 4.000 505.600 796.000 513.720 ;
        RECT 4.000 504.200 795.600 505.600 ;
        RECT 4.000 496.080 796.000 504.200 ;
        RECT 4.400 494.680 796.000 496.080 ;
        RECT 4.000 486.560 796.000 494.680 ;
        RECT 4.000 485.160 795.600 486.560 ;
        RECT 4.000 477.040 796.000 485.160 ;
        RECT 4.400 475.640 796.000 477.040 ;
        RECT 4.000 467.520 796.000 475.640 ;
        RECT 4.000 466.120 795.600 467.520 ;
        RECT 4.000 458.000 796.000 466.120 ;
        RECT 4.400 456.600 796.000 458.000 ;
        RECT 4.000 448.480 796.000 456.600 ;
        RECT 4.000 447.080 795.600 448.480 ;
        RECT 4.000 438.960 796.000 447.080 ;
        RECT 4.400 437.560 796.000 438.960 ;
        RECT 4.000 429.440 796.000 437.560 ;
        RECT 4.000 428.040 795.600 429.440 ;
        RECT 4.000 419.920 796.000 428.040 ;
        RECT 4.400 418.520 796.000 419.920 ;
        RECT 4.000 410.400 796.000 418.520 ;
        RECT 4.000 409.000 795.600 410.400 ;
        RECT 4.000 400.880 796.000 409.000 ;
        RECT 4.400 399.480 796.000 400.880 ;
        RECT 4.000 391.360 796.000 399.480 ;
        RECT 4.000 389.960 795.600 391.360 ;
        RECT 4.000 381.840 796.000 389.960 ;
        RECT 4.400 380.440 796.000 381.840 ;
        RECT 4.000 372.320 796.000 380.440 ;
        RECT 4.000 370.920 795.600 372.320 ;
        RECT 4.000 362.800 796.000 370.920 ;
        RECT 4.400 361.400 796.000 362.800 ;
        RECT 4.000 353.280 796.000 361.400 ;
        RECT 4.000 351.880 795.600 353.280 ;
        RECT 4.000 343.760 796.000 351.880 ;
        RECT 4.400 342.360 796.000 343.760 ;
        RECT 4.000 334.240 796.000 342.360 ;
        RECT 4.000 332.840 795.600 334.240 ;
        RECT 4.000 324.720 796.000 332.840 ;
        RECT 4.400 323.320 796.000 324.720 ;
        RECT 4.000 315.200 796.000 323.320 ;
        RECT 4.000 313.800 795.600 315.200 ;
        RECT 4.000 305.680 796.000 313.800 ;
        RECT 4.400 304.280 796.000 305.680 ;
        RECT 4.000 296.160 796.000 304.280 ;
        RECT 4.000 294.760 795.600 296.160 ;
        RECT 4.000 286.640 796.000 294.760 ;
        RECT 4.400 285.240 796.000 286.640 ;
        RECT 4.000 277.120 796.000 285.240 ;
        RECT 4.000 275.720 795.600 277.120 ;
        RECT 4.000 267.600 796.000 275.720 ;
        RECT 4.400 266.200 796.000 267.600 ;
        RECT 4.000 258.080 796.000 266.200 ;
        RECT 4.000 256.680 795.600 258.080 ;
        RECT 4.000 248.560 796.000 256.680 ;
        RECT 4.400 247.160 796.000 248.560 ;
        RECT 4.000 239.040 796.000 247.160 ;
        RECT 4.000 237.640 795.600 239.040 ;
        RECT 4.000 229.520 796.000 237.640 ;
        RECT 4.400 228.120 796.000 229.520 ;
        RECT 4.000 220.000 796.000 228.120 ;
        RECT 4.000 218.600 795.600 220.000 ;
        RECT 4.000 210.480 796.000 218.600 ;
        RECT 4.400 209.080 796.000 210.480 ;
        RECT 4.000 200.960 796.000 209.080 ;
        RECT 4.000 199.560 795.600 200.960 ;
        RECT 4.000 191.440 796.000 199.560 ;
        RECT 4.400 190.040 796.000 191.440 ;
        RECT 4.000 181.920 796.000 190.040 ;
        RECT 4.000 180.520 795.600 181.920 ;
        RECT 4.000 172.400 796.000 180.520 ;
        RECT 4.400 171.000 796.000 172.400 ;
        RECT 4.000 162.880 796.000 171.000 ;
        RECT 4.000 161.480 795.600 162.880 ;
        RECT 4.000 153.360 796.000 161.480 ;
        RECT 4.400 151.960 796.000 153.360 ;
        RECT 4.000 143.840 796.000 151.960 ;
        RECT 4.000 142.440 795.600 143.840 ;
        RECT 4.000 134.320 796.000 142.440 ;
        RECT 4.400 132.920 796.000 134.320 ;
        RECT 4.000 124.800 796.000 132.920 ;
        RECT 4.000 123.400 795.600 124.800 ;
        RECT 4.000 115.280 796.000 123.400 ;
        RECT 4.400 113.880 796.000 115.280 ;
        RECT 4.000 105.760 796.000 113.880 ;
        RECT 4.000 104.360 795.600 105.760 ;
        RECT 4.000 96.240 796.000 104.360 ;
        RECT 4.400 94.840 796.000 96.240 ;
        RECT 4.000 86.720 796.000 94.840 ;
        RECT 4.000 85.320 795.600 86.720 ;
        RECT 4.000 77.200 796.000 85.320 ;
        RECT 4.400 75.800 796.000 77.200 ;
        RECT 4.000 67.680 796.000 75.800 ;
        RECT 4.000 66.280 795.600 67.680 ;
        RECT 4.000 58.160 796.000 66.280 ;
        RECT 4.400 56.760 796.000 58.160 ;
        RECT 4.000 48.640 796.000 56.760 ;
        RECT 4.000 47.240 795.600 48.640 ;
        RECT 4.000 39.120 796.000 47.240 ;
        RECT 4.400 37.720 796.000 39.120 ;
        RECT 4.000 29.600 796.000 37.720 ;
        RECT 4.000 28.200 795.600 29.600 ;
        RECT 4.000 20.080 796.000 28.200 ;
        RECT 4.400 18.680 796.000 20.080 ;
        RECT 4.000 8.335 796.000 18.680 ;
      LAYER met4 ;
        RECT 35.255 581.405 174.240 635.625 ;
        RECT 176.640 581.405 177.540 635.625 ;
        RECT 179.940 581.405 327.840 635.625 ;
        RECT 35.255 363.395 327.840 581.405 ;
        RECT 35.255 281.405 174.240 363.395 ;
        RECT 176.640 281.405 177.540 363.395 ;
        RECT 179.940 281.405 327.840 363.395 ;
        RECT 35.255 63.395 327.840 281.405 ;
        RECT 35.255 10.240 174.240 63.395 ;
        RECT 176.640 10.240 177.540 63.395 ;
        RECT 179.940 10.240 327.840 63.395 ;
        RECT 330.240 10.240 331.140 635.625 ;
        RECT 333.540 581.405 481.440 635.625 ;
        RECT 483.840 581.405 484.740 635.625 ;
        RECT 487.140 581.405 635.040 635.625 ;
        RECT 333.540 457.600 635.040 581.405 ;
        RECT 333.540 445.440 610.140 457.600 ;
        RECT 612.540 445.440 635.040 457.600 ;
        RECT 333.540 414.080 635.040 445.440 ;
        RECT 333.540 363.395 610.140 414.080 ;
        RECT 333.540 281.405 481.440 363.395 ;
        RECT 483.840 281.405 484.740 363.395 ;
        RECT 487.140 336.640 610.140 363.395 ;
        RECT 612.540 336.640 635.040 414.080 ;
        RECT 487.140 283.520 635.040 336.640 ;
        RECT 487.140 281.405 610.140 283.520 ;
        RECT 333.540 108.160 610.140 281.405 ;
        RECT 612.540 108.160 635.040 283.520 ;
        RECT 333.540 63.395 635.040 108.160 ;
        RECT 333.540 10.240 481.440 63.395 ;
        RECT 483.840 10.240 484.740 63.395 ;
        RECT 487.140 55.040 635.040 63.395 ;
        RECT 487.140 42.880 610.140 55.040 ;
        RECT 612.540 42.880 635.040 55.040 ;
        RECT 487.140 10.240 635.040 42.880 ;
        RECT 637.440 10.240 638.340 635.625 ;
        RECT 640.740 10.240 769.745 635.625 ;
        RECT 35.255 8.335 769.745 10.240 ;
      LAYER met5 ;
        RECT 55.280 492.770 761.180 534.810 ;
        RECT 55.280 339.590 761.180 484.670 ;
        RECT 55.280 186.410 761.180 331.490 ;
        RECT 55.280 51.900 761.180 178.310 ;
  END
END pipelined_mult
END LIBRARY

